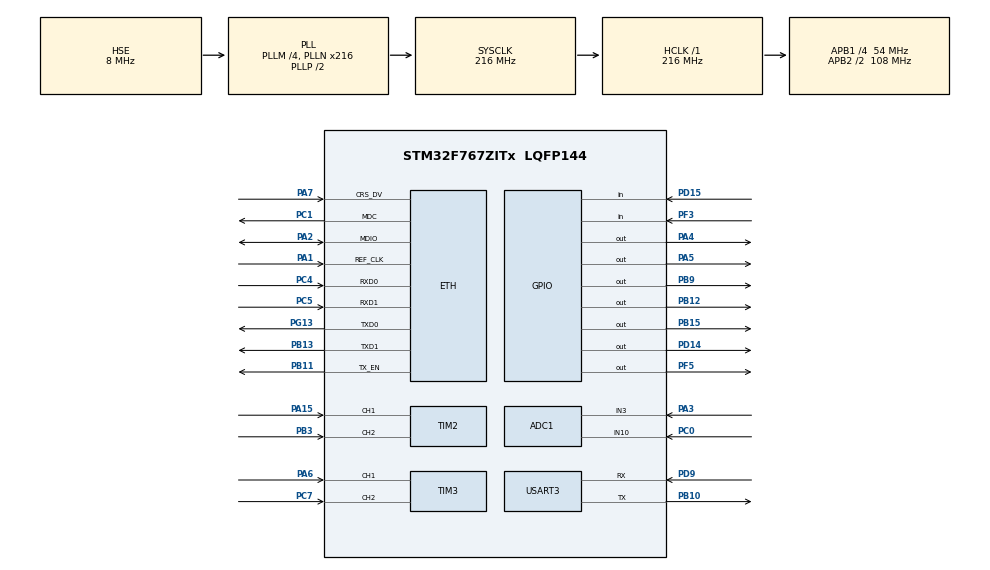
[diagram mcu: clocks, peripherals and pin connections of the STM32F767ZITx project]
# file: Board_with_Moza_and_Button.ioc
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ADC1.Channel-0\#ChannelRegularConversion=ADC_CHANNEL_3
ADC1.ClockPrescaler=ADC_CLOCK_SYNC_PCLK_DIV6
ADC1.NbrOfConversion=1
ADC1.NbrOfConversionFlag=1
ADC1.Rank-0\#ChannelRegularConversion=1
ADC1.SamplingTime-0\#ChannelRegularConversion=ADC_SAMPLETIME_3CYCLES
ADC1.master=1
CORTEX_M7.default_mode_Activation=1
ETH.MediaInterface=HAL_ETH_RMII_MODE
LWIP.BSP.number=1
LWIP.LWIP_DHCP=0
LWIP.Version=v2.1.2_Cube
LWIP0.BSP.STBoard=false
LWIP0.BSP.api=BSP_COMPONENT_DRIVER
LWIP0.BSP.component=LAN8742
LWIP0.BSP.instance=LAN8742
LWIP0.BSP.name=Driver_PHY
LWIP0.BSP.semaphore=S_LAN8742
LWIP0.BSP.solution=LAN8742
Mcu.Family=STM32F7
Mcu.Name=STM32F767ZITx
Mcu.Package=LQFP144
NVIC.PriorityGroup=NVIC_PRIORITYGROUP_4
PA1.Mode=RMII
PA1.Signal=ETH_REF_CLK
PA15.GPIO_PuPd=GPIO_PULLUP
PA15.Signal=S_TIM2_CH1_ETR
PA2.Mode=RMII
PA2.Signal=ETH_MDIO
PA3.Signal=ADCx_IN3
PA4.PinState=GPIO_PIN_SET
PA4.Signal=GPIO_Output
PA5.Signal=GPIO_Output
PA6.GPIO_PuPd=GPIO_PULLUP
PA6.Signal=S_TIM3_CH1
PA7.Mode=RMII
PA7.Signal=ETH_CRS_DV
PB10.Mode=Asynchronous
PB10.Signal=USART3_TX
PB11.Mode=RMII
PB11.Signal=ETH_TX_EN
PB12.PinState=GPIO_PIN_SET
PB12.Signal=GPIO_Output
PB13.Mode=RMII
PB13.Signal=ETH_TXD1
PB15.Signal=GPIO_Output
PB3.GPIO_PuPd=GPIO_PULLUP
PB3.Signal=S_TIM2_CH2
PB9.PinState=GPIO_PIN_SET
PB9.Signal=GPIO_Output
PC0.Signal=ADCx_IN10
PC1.Mode=RMII
PC1.Signal=ETH_MDC
PC4.Mode=RMII
PC4.Signal=ETH_RXD0
PC5.Mode=RMII
PC5.Signal=ETH_RXD1
PC7.GPIO_PuPd=GPIO_PULLUP
PC7.Signal=S_TIM3_CH2
PD14.PinState=GPIO_PIN_SET
PD14.Signal=GPIO_Output
PD15.GPIO_PuPd=GPIO_PULLUP
PD15.Signal=GPIO_Input
PD9.Mode=Asynchronous
PD9.Signal=USART3_RX
PF3.Signal=GPIO_Input
PF5.Signal=GPIO_Output
PG13.Mode=RMII
PG13.Signal=ETH_TXD0
PH0/OSC_IN.Mode=HSE-External-Clock-Source
PH0/OSC_IN.Signal=RCC_OSC_IN
PH1/OSC_OUT.Mode=HSE-External-Clock-Source
PH1/OSC_OUT.Signal=RCC_OSC_OUT
ProjectManager.HeapSize=0x200
ProjectManager.StackSize=0x400
ProjectManager.TargetToolchain=STM32CubeIDE
RCC.AHBFreq_Value=216000000
RCC.APB1CLKDivider=RCC_HCLK_DIV4
RCC.APB1Freq_Value=54000000
RCC.APB1TimFreq_Value=108000000
RCC.APB2CLKDivider=RCC_HCLK_DIV2
RCC.APB2Freq_Value=108000000
RCC.APB2TimFreq_Value=216000000
RCC.CortexFreq_Value=216000000
RCC.HCLKFreq_Value=216000000
RCC.HSE_VALUE=8000000
RCC.HSI_VALUE=16000000
RCC.LSE_VALUE=32768
RCC.PLLM=4
RCC.PLLN=216
RCC.PLLSourceVirtual=RCC_PLLSOURCE_HSE
RCC.SYSCLKFreq_VALUE=216000000
RCC.SYSCLKSource=RCC_SYSCLKSOURCE_PLLCLK
RCC.USBFreq_Value=216000000
RCC.VCOOutputFreq_Value=432000000
SH.ADCx_IN10.0=ADC1_IN10,IN10
SH.ADCx_IN3.0=ADC1_IN3,IN3
SH.S_TIM2_CH1_ETR.0=TIM2_CH1,Encoder_Interface
SH.S_TIM2_CH2.0=TIM2_CH2,Encoder_Interface
SH.S_TIM3_CH1.0=TIM3_CH1,Encoder_Interface
SH.S_TIM3_CH2.0=TIM3_CH2,Encoder_Interface
TIM3.EncoderMode=TIM_ENCODERMODE_TI12
USART3.VirtualMode-Asynchronous=VM_ASYNC
VP_LWIP_VS_Enabled.Mode=Enabled
board=custom

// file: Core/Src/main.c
/* USER CODE BEGIN Header */
/**
  ******************************************************************************
  * @file           : main.c
  * @brief          : Sim Rig Controller - Moza pedals (TLE5012 halls + HX711)
  *
  * Pin map (pedals + shifter, shared SSC bus):
  *   SCK   PA5      DATA  PB15
  *   CS Throttle PA4   CS Clutch PB9   CS Brake PB12   CS Gearbox PD14
  *   HX711 DOUT PF3    HX711 SCK PF5
  * Encoders: TIM2 -> PA15/PB3 (Left), TIM3 -> PA6/PC7 (Right)
  * Gearbox halls: H1 PA3 (ADC1_IN3), H2 PC0 (ADC1_IN10)
  ******************************************************************************
  */
/* USER CODE END Header */

#include "main.h"
#include "lwip.h"
#include <stdlib.h>

/* USER CODE BEGIN Includes */
#include "udp_server.h"
#include <stdio.h>
#include "Tle5012b.h"
#include "hx711.h"
/* USER CODE END Includes */

/* USER CODE BEGIN PD */
/* Moza pedal calibration (angles in degrees from TLE5012) */
#define THROTTLE_ANGLE_MIN     -138.23f
#define THROTTLE_ANGLE_MAX     -118.54f
#define CLUTCH_ANGLE_MIN       -5.83f
#define CLUTCH_ANGLE_MAX       13.16f
#define BRAKE_HALL_ANGLE_MIN   -133.11f
#define BRAKE_HALL_ANGLE_MAX   -121.36f
#define BRAKE_LOADCELL_MIN     -420000
#define BRAKE_LOADCELL_MAX     3600000
#define BRAKE_LOADCELL_TRUST   0.5f

#define RIGHT_STICK_MIN   0
#define RIGHT_STICK_MAX   -475

#define LEFT_STICK_MIN    0
#define LEFT_STICK_MAX    490
/* USER CODE END PD */

ADC_HandleTypeDef hadc1;

UART_HandleTypeDef huart3;

TIM_HandleTypeDef htim2; // Left encoder
TIM_HandleTypeDef htim3; // Right encoder

/* USER CODE BEGIN PV */
/* Global Variables exported to UDP/System (names/types unchanged) */
volatile int32_t current_gear = 0;
volatile int32_t encoder_position = 0;  // Left  (TIM2)
volatile int32_t encoder2_position = 0; // Right (TIM3)

volatile int32_t accelerator_position = 0; // throttle angle * 100
volatile int32_t brake_position = 0;       // filtered load cell raw
volatile int32_t clutch_position = 0;      // clutch angle * 100

volatile int32_t button_state = 0; // 0 = Released, 1 = Pressed

volatile float right_stick_scaled = 0.0f;
volatile float left_stick_scaled  = 0.0f;
volatile float accelerator_scaled = 0.0f;
volatile float brake_scaled       = 0.0f;   // final blended brake (hall + load cell)
volatile float clutch_scaled      = 0.0f;
volatile float min_clutch_pressed = 0.8f;

uint32_t H1_ADC = 0;
uint32_t H2_ADC = 0;

/* Pedal sensor data */
static float throttle_angle   = 0.0f;
static float clutch_angle     = 0.0f;
static float brake_hall_angle = 0.0f;
static float brake_hall_scaled = 0.0f;
static TLE5012_Frame_t throttle_frame, clutch_frame, brake_hall_frame;

static int32_t loadcell_filtered = 0;
static uint8_t loadcell_filter_init = 0;

/* Internal Loop State Variables */
static uint32_t last_tick_ms = 0;
static uint32_t last_led_tick_ms = 0;
static uint32_t last_uart_tick_ms = 0;

static uint16_t last_timer = 0;
static uint16_t last_timer2 = 0;

static uint32_t h1_filtered = 0, h2_filtered = 0;
static uint8_t  h1_filter_init = 0, h2_filter_init = 0;

static int32_t last_valid_gear = 0;
static int32_t last_requested_gear = 0;

static int32_t h_fused = 0;
/* USER CODE END PV */

void SystemClock_Config(void);
static void MPU_Config(void);
static void MX_GPIO_Init(void);
static void MX_ADC1_Init(void);
static void MX_TIM2_Init(void);
static void MX_TIM3_Init(void);
static void MX_USART3_UART_Init(void);

/* USER CODE BEGIN PFP */
static uint32_t read_adc_channel(ADC_HandleTypeDef *hadc, uint32_t channel);
static float scale_clamped_0_1(float value, float min_val, float max_val);
static void read_pedal_angle(const TLE5012_Sensor_t *s, float *angle, TLE5012_Frame_t *frame);
static int32_t compute_gear(float x_raw, int32_t y_raw);
/* USER CODE END PFP */

/* USER CODE BEGIN 0 */
static uint32_t read_adc_channel(ADC_HandleTypeDef *hadc, uint32_t channel)
{
    ADC_ChannelConfTypeDef sConfig = {0};
    sConfig.Channel = channel;
    sConfig.Rank = ADC_REGULAR_RANK_1;
    sConfig.SamplingTime = ADC_SAMPLETIME_56CYCLES;
    HAL_ADC_ConfigChannel(hadc, &sConfig);

    HAL_ADC_Start(hadc);
    HAL_ADC_PollForConversion(hadc, 10);
    uint32_t raw = HAL_ADC_GetValue(hadc);
    HAL_ADC_Stop(hadc);

    return raw;
}

/* Works for both min<max and min>max (reversed) ranges */
static float scale_clamped_0_1(float value, float min_val, float max_val)
{
    if (min_val == max_val) return 0.0f;

    float lo = (min_val < max_val) ? min_val : max_val;
    float hi = (min_val < max_val) ? max_val : min_val;
    if (value < lo) value = lo;
    if (value > hi) value = hi;

    return (value - min_val) / (max_val - min_val);
}

/* Reads a TLE5012 angle; keeps the previous angle if the CRC check fails */
static void read_pedal_angle(const TLE5012_Sensor_t *s, float *angle, TLE5012_Frame_t *frame)
{
    float a = 0.0f;
    TLE5012_Frame_t f;
    if (TLE5012_ReadAngleDeg(s, &a, &f) == HAL_OK && f.crc_ok) {
        *angle = a;
    }
    *frame = f;
}

static int classify_row(int32_t y)
{
    if (y < -1500) return -1;      /* top (front) */
    else if (y > 1500) return 1;   /* neutral */
    else return 0;                 /* bottom (back) */
}

static int classify_col(float x)
{
    if (x < -58.0f) return -1;     /* left */
    else if (x < -48.0f) return 0; /* center */
    else return 1;                 /* right */
}

static int32_t compute_gear(float x_raw, int32_t y_raw)
{
    int col = classify_col(x_raw);
    int row = classify_row(y_raw);

    if (row == 0) return 0;

    if (row == -1) {
        if (col == -1) return 3;
        if (col == 0)  return 6;
        if (col == 1)  return 4;
    }

    if (row == 1) {
        if (col == -1) return 2;
        if (col == 0)  return 1;
        if (col == 1)  return 5;
    }

    return 0;
}
/* USER CODE END 0 */

int main(void)
{
  TLE5012_Frame_t frame = {0};
  float angle_deg = 0.0f;

  MPU_Config();
  HAL_Init();
  SystemClock_Config();

  /* Peripheral Initialization */
  MX_GPIO_Init();
  MX_ADC1_Init();
  MX_TIM2_Init();
  MX_TIM3_Init();
  MX_USART3_UART_Init();
  MX_LWIP_Init();

  HAL_Delay(500);

  /* Start Hardware Timers for Quadrature Encoders */
  HAL_TIM_Encoder_Start(&htim2, TIM_CHANNEL_ALL); // Left
  HAL_TIM_Encoder_Start(&htim3, TIM_CHANNEL_ALL); // Right
  last_timer  = (uint16_t)__HAL_TIM_GET_COUNTER(&htim2);
  last_timer2 = (uint16_t)__HAL_TIM_GET_COUNTER(&htim3);

  /* Initialize Communication and Driver Peripherals */
  udp_server_init();
  TLE5012_GPIO_Init();   /* SCK/DATA + 4 CS lines (idle HIGH) + DWT */
  HX711_Init();          /* PF5 SCK, PF3 DOUT */

  uint32_t init_tick = HAL_GetTick();
  last_tick_ms      = init_tick;
  last_led_tick_ms  = init_tick;
  last_uart_tick_ms = init_tick;

  while (1)
  {
      MX_LWIP_Process();
      uint32_t now = HAL_GetTick();

      /* 1. Heartbeat LED (500ms Period) */
      if ((now - last_led_tick_ms) >= 500) {
          HAL_GPIO_TogglePin(LD2_GPIO_Port, LD2_Pin);
          last_led_tick_ms = now;
      }

      /* 2. Main Input Sampling Loop (10ms / 100Hz Rate) */
      if ((now - last_tick_ms) >= 10)
      {
          last_tick_ms = now;

          /* Push Button on PD15 (Active Low) */
          button_state = (HAL_GPIO_ReadPin(GPIOD, GPIO_PIN_15) == GPIO_PIN_RESET) ? 1 : 0;

          /* Left Encoder (TIM2) */
          uint16_t current_timer = (uint16_t)__HAL_TIM_GET_COUNTER(&htim2);
          encoder_position += (int16_t)(current_timer - last_timer);
          last_timer = current_timer;

          /* Right Encoder (TIM3) */
          uint16_t current_timer2 = (uint16_t)__HAL_TIM_GET_COUNTER(&htim3);
          encoder2_position += (int16_t)(current_timer2 - last_timer2);
          last_timer2 = current_timer2;

          /* ---------- Moza pedals ---------- */
          read_pedal_angle(&TLE5012_THROTTLE,   &throttle_angle,   &throttle_frame);
          read_pedal_angle(&TLE5012_CLUTCH,     &clutch_angle,     &clutch_frame);
          read_pedal_angle(&TLE5012_BRAKE_HALL, &brake_hall_angle, &brake_hall_frame);

          /* Load cell: non-blocking, only reads when a conversion is ready */
          int32_t lc_raw;
          if (HX711_TryRead(HX711_CHA_GAIN_128, &lc_raw)) {
              if (!loadcell_filter_init) { loadcell_filtered = lc_raw; loadcell_filter_init = 1; }
              else { loadcell_filtered += (lc_raw - loadcell_filtered) / 8; }
          }

          brake_hall_scaled = scale_clamped_0_1(brake_hall_angle,
                                                BRAKE_HALL_ANGLE_MIN, BRAKE_HALL_ANGLE_MAX);
          float loadcell_scaled = scale_clamped_0_1((float)loadcell_filtered,
                                                    BRAKE_LOADCELL_MIN, BRAKE_LOADCELL_MAX);

          accelerator_scaled = scale_clamped_0_1(throttle_angle, THROTTLE_ANGLE_MIN, THROTTLE_ANGLE_MAX);
          clutch_scaled      = scale_clamped_0_1(clutch_angle,   CLUTCH_ANGLE_MIN,   CLUTCH_ANGLE_MAX);
          brake_scaled       = brake_hall_scaled * (1.0f - BRAKE_LOADCELL_TRUST)
                             + loadcell_scaled   * BRAKE_LOADCELL_TRUST;

          /* Keep the raw-position fields populated for UDP/debug users */
          accelerator_position = (int32_t)(throttle_angle * 100.0f);
          clutch_position      = (int32_t)(clutch_angle   * 100.0f);
          brake_position       = loadcell_filtered;

          /* Encoder Normalization */
          left_stick_scaled  = scale_clamped_0_1((float)encoder_position,  LEFT_STICK_MIN,  LEFT_STICK_MAX);  // TIM2 = Left
          right_stick_scaled = scale_clamped_0_1((float)encoder2_position, RIGHT_STICK_MIN, RIGHT_STICK_MAX); // TIM3 = Right

          /* Gearbox Hall Sensors */
          H1_ADC = read_adc_channel(&hadc1, ADC_CHANNEL_3);
          H2_ADC = read_adc_channel(&hadc1, ADC_CHANNEL_10);

          if (!h1_filter_init) { h1_filtered = H1_ADC; h1_filter_init = 1; }
          else { h1_filtered = h1_filtered + ((int32_t)H1_ADC - (int32_t)h1_filtered) / 3; }

          if (!h2_filter_init) { h2_filtered = H2_ADC; h2_filter_init = 1; }
          else { h2_filtered = h2_filtered + ((int32_t)H2_ADC - (int32_t)h2_filtered) / 3; }

          h_fused = (int32_t)h1_filtered - (int32_t)h2_filtered;

          /* TLE5012 Shifter Angle Decoding */
          if (TLE5012_ReadAngleDeg(&TLE5012_GEARBOX, &angle_deg, &frame) == HAL_OK && frame.crc_ok) {
              int32_t requested_gear = compute_gear(angle_deg, h_fused);

              if (requested_gear != last_requested_gear) {
                  if (clutch_scaled >= min_clutch_pressed) {
                      last_valid_gear = requested_gear;
                  }
                  last_requested_gear = requested_gear;
              }
              current_gear = last_valid_gear;
          }
          else {
              current_gear = last_valid_gear;
          }

          udp_server_send_position();
      }

      /* 3. Debug Output via UART3 (200ms Rate) */
      if ((now - last_uart_tick_ms) >= 200) {
          last_uart_tick_ms = now;
          char dbg[360];
          int dbg_len = snprintf(dbg, sizeof(dbg),
              "Acc:%.2f (Ang:%.2f CRC:%u) Clt:%.2f (Ang:%.2f CRC:%u) "
              "Brk:%.2f (Hall:%.2f Ang:%.2f CRC:%u LC:%ld) "
              "H1:%lu H2:%lu h_fused:%ld Angle:%.2f Gear:%ld "
              "RT:%.2f (Raw2:%ld) LT:%.2f (Raw:%ld) Btn:%ld\r\n",
              accelerator_scaled, throttle_angle, throttle_frame.crc_ok,
              clutch_scaled, clutch_angle, clutch_frame.crc_ok,
              brake_scaled, brake_hall_scaled, brake_hall_angle, brake_hall_frame.crc_ok,
              (long)loadcell_filtered,
              H1_ADC, H2_ADC, (long)h_fused, angle_deg, (long)current_gear,
              right_stick_scaled, (long)encoder2_position,
              left_stick_scaled, (long)encoder_position, (long)button_state);
          if (dbg_len > (int)sizeof(dbg)) dbg_len = sizeof(dbg);
          HAL_UART_Transmit(&huart3, (uint8_t*)dbg, dbg_len, 50);
      }
  }
}

void SystemClock_Config(void)
{
  RCC_OscInitTypeDef RCC_OscInitStruct = {0};
  RCC_ClkInitTypeDef RCC_ClkInitStruct = {0};

  HAL_PWR_EnableBkUpAccess();
  __HAL_RCC_PWR_CLK_ENABLE();
  __HAL_PWR_VOLTAGESCALING_CONFIG(PWR_REGULATOR_VOLTAGE_SCALE1);

  RCC_OscInitStruct.OscillatorType = RCC_OSCILLATORTYPE_HSE;
  RCC_OscInitStruct.HSEState = RCC_HSE_BYPASS;
  RCC_OscInitStruct.PLL.PLLState = RCC_PLL_ON;
  RCC_OscInitStruct.PLL.PLLSource = RCC_PLLSOURCE_HSE;
  RCC_OscInitStruct.PLL.PLLM = 4;
  RCC_OscInitStruct.PLL.PLLN = 216;
  RCC_OscInitStruct.PLL.PLLP = RCC_PLLP_DIV2;
  RCC_OscInitStruct.PLL.PLLQ = 9;
  RCC_OscInitStruct.PLL.PLLR = 2;

  // Retry until the external MCO/HSE is actually present
  while (HAL_RCC_OscConfig(&RCC_OscInitStruct) != HAL_OK)
  {
      HAL_Delay(5); // safe: still running off default HSI here
  }

  if (HAL_PWREx_EnableOverDrive() != HAL_OK) { Error_Handler(); }

  RCC_ClkInitStruct.ClockType = RCC_CLOCKTYPE_HCLK|RCC_CLOCKTYPE_SYSCLK
                              |RCC_CLOCKTYPE_PCLK1|RCC_CLOCKTYPE_PCLK2;
  RCC_ClkInitStruct.SYSCLKSource = RCC_SYSCLKSOURCE_PLLCLK;
  RCC_ClkInitStruct.AHBCLKDivider = RCC_SYSCLK_DIV1;
  RCC_ClkInitStruct.APB1CLKDivider = RCC_HCLK_DIV4;
  RCC_ClkInitStruct.APB2CLKDivider = RCC_HCLK_DIV2;

  while (HAL_RCC_ClockConfig(&RCC_ClkInitStruct, FLASH_LATENCY_7) != HAL_OK)
  {
      HAL_Delay(5);
  }
}

/* ADC1: gearbox hall sensors only (H1 = CH3, H2 = CH10, switched at runtime) */
static void MX_ADC1_Init(void)
{
  ADC_ChannelConfTypeDef sConfig = {0};

  hadc1.Instance = ADC1;
  hadc1.Init.ClockPrescaler = ADC_CLOCK_SYNC_PCLK_DIV6;
  hadc1.Init.Resolution = ADC_RESOLUTION_12B;
  hadc1.Init.ScanConvMode = ADC_SCAN_DISABLE;
  hadc1.Init.ContinuousConvMode = DISABLE;
  hadc1.Init.DiscontinuousConvMode = DISABLE;
  hadc1.Init.ExternalTrigConvEdge = ADC_EXTERNALTRIGCONVEDGE_NONE;
  hadc1.Init.ExternalTrigConv = ADC_SOFTWARE_START;
  hadc1.Init.DataAlign = ADC_DATAALIGN_RIGHT;
  hadc1.Init.NbrOfConversion = 1;
  hadc1.Init.DMAContinuousRequests = DISABLE;
  hadc1.Init.EOCSelection = ADC_EOC_SINGLE_CONV;
  if (HAL_ADC_Init(&hadc1) != HAL_OK)
  {
    Error_Handler();
  }

  sConfig.Channel = ADC_CHANNEL_3;
  sConfig.Rank = ADC_REGULAR_RANK_1;
  sConfig.SamplingTime = ADC_SAMPLETIME_3CYCLES;
  if (HAL_ADC_ConfigChannel(&hadc1, &sConfig) != HAL_OK)
  {
    Error_Handler();
  }
}

static void MX_TIM2_Init(void)
{
  TIM_Encoder_InitTypeDef sConfig = {0};
  TIM_MasterConfigTypeDef sMasterConfig = {0};

  htim2.Instance = TIM2;
  htim2.Init.Prescaler = 0;
  htim2.Init.CounterMode = TIM_COUNTERMODE_UP;
  htim2.Init.Period = 65535;
  htim2.Init.ClockDivision = TIM_CLOCKDIVISION_DIV1;
  htim2.Init.AutoReloadPreload = TIM_AUTORELOAD_PRELOAD_DISABLE;
  sConfig.EncoderMode = TIM_ENCODERMODE_TI12;
  sConfig.IC1Polarity = TIM_ICPOLARITY_RISING;
  sConfig.IC1Selection = TIM_ICSELECTION_DIRECTTI;
  sConfig.IC1Prescaler = TIM_ICPSC_DIV1;
  sConfig.IC1Filter = 0;
  sConfig.IC2Polarity = TIM_ICPOLARITY_RISING;
  sConfig.IC2Selection = TIM_ICSELECTION_DIRECTTI;
  sConfig.IC2Prescaler = TIM_ICPSC_DIV1;
  sConfig.IC2Filter = 0;
  if (HAL_TIM_Encoder_Init(&htim2, &sConfig) != HAL_OK)
  {
    Error_Handler();
  }
  sMasterConfig.MasterOutputTrigger = TIM_TRGO_RESET;
  sMasterConfig.MasterSlaveMode = TIM_MASTERSLAVEMODE_DISABLE;
  if (HAL_TIMEx_MasterConfigSynchronization(&htim2, &sMasterConfig) != HAL_OK)
  {
    Error_Handler();
  }
}

static void MX_TIM3_Init(void)
{
  TIM_Encoder_InitTypeDef sConfig = {0};
  TIM_MasterConfigTypeDef sMasterConfig = {0};

  htim3.Instance = TIM3;
  htim3.Init.Prescaler = 0;
  htim3.Init.CounterMode = TIM_COUNTERMODE_UP;
  htim3.Init.Period = 65535;
  htim3.Init.ClockDivision = TIM_CLOCKDIVISION_DIV1;
  htim3.Init.AutoReloadPreload = TIM_AUTORELOAD_PRELOAD_DISABLE;
  sConfig.EncoderMode = TIM_ENCODERMODE_TI12;
  sConfig.IC1Polarity = TIM_ICPOLARITY_RISING;
  sConfig.IC1Selection = TIM_ICSELECTION_DIRECTTI;
  sConfig.IC1Prescaler = TIM_ICPSC_DIV1;
  sConfig.IC1Filter = 0;
  sConfig.IC2Polarity = TIM_ICPOLARITY_RISING;
  sConfig.IC2Selection = TIM_ICSELECTION_DIRECTTI;
  sConfig.IC2Prescaler = TIM_ICPSC_DIV1;
  sConfig.IC2Filter = 0;
  if (HAL_TIM_Encoder_Init(&htim3, &sConfig) != HAL_OK)
  {
    Error_Handler();
  }
  sMasterConfig.MasterOutputTrigger = TIM_TRGO_RESET;
  sMasterConfig.MasterSlaveMode = TIM_MASTERSLAVEMODE_DISABLE;
  if (HAL_TIMEx_MasterConfigSynchronization(&htim3, &sMasterConfig) != HAL_OK)
  {
    Error_Handler();
  }
}

static void MX_USART3_UART_Init(void)
{
  huart3.Instance = USART3;
  huart3.Init.BaudRate = 115200;
  huart3.Init.WordLength = UART_WORDLENGTH_8B;
  huart3.Init.StopBits = UART_STOPBITS_1;
  huart3.Init.Parity = UART_PARITY_NONE;
  huart3.Init.Mode = UART_MODE_TX_RX;
  huart3.Init.HwFlowCtl = UART_HWCONTROL_NONE;
  huart3.Init.OverSampling = UART_OVERSAMPLING_16;
  huart3.Init.OneBitSampling = UART_ONE_BIT_SAMPLE_DISABLE;
  huart3.AdvancedInit.AdvFeatureInit = UART_ADVFEATURE_NO_INIT;
  if (HAL_UART_Init(&huart3) != HAL_OK)
  {
    Error_Handler();
  }
}

static void MX_GPIO_Init(void)
{
  GPIO_InitTypeDef GPIO_InitStruct = {0};

  __HAL_RCC_GPIOC_CLK_ENABLE();
  __HAL_RCC_GPIOF_CLK_ENABLE();
  __HAL_RCC_GPIOH_CLK_ENABLE();
  __HAL_RCC_GPIOA_CLK_ENABLE();
  __HAL_RCC_GPIOB_CLK_ENABLE();
  __HAL_RCC_GPIOD_CLK_ENABLE();
  __HAL_RCC_GPIOG_CLK_ENABLE();
  __HAL_RCC_SYSCFG_CLK_ENABLE();

  HAL_GPIO_WritePin(GPIOB, LD1_Pin|LD3_Pin|LD2_Pin, GPIO_PIN_RESET);
  /* PD14 = Gearbox TLE5012 CS (active LOW) -> idle HIGH (deselected) */
  HAL_GPIO_WritePin(GPIOD, GPIO_PIN_14, GPIO_PIN_SET);
  HAL_GPIO_WritePin(USB_PowerSwitchOn_GPIO_Port, USB_PowerSwitchOn_Pin, GPIO_PIN_RESET);

  /* Configure PD15 as Input with Internal Pull-Up for Push Button */
  GPIO_InitStruct.Pin = GPIO_PIN_15;
  GPIO_InitStruct.Mode = GPIO_MODE_INPUT;
  GPIO_InitStruct.Pull = GPIO_PULLUP;
  HAL_GPIO_Init(GPIOD, &GPIO_InitStruct);

  GPIO_InitStruct.Pin = LD1_Pin|LD3_Pin|LD2_Pin;
  GPIO_InitStruct.Mode = GPIO_MODE_OUTPUT_PP;
  GPIO_InitStruct.Pull = GPIO_NOPULL;
  GPIO_InitStruct.Speed = GPIO_SPEED_FREQ_LOW;
  HAL_GPIO_Init(GPIOB, &GPIO_InitStruct);

  GPIO_InitStruct.Pin = GPIO_PIN_14;
  GPIO_InitStruct.Mode = GPIO_MODE_OUTPUT_PP;
  GPIO_InitStruct.Pull = GPIO_NOPULL;
  GPIO_InitStruct.Speed = GPIO_SPEED_FREQ_LOW;
  HAL_GPIO_Init(GPIOD, &GPIO_InitStruct);

  GPIO_InitStruct.Pin = USB_PowerSwitchOn_Pin;
  GPIO_InitStruct.Mode = GPIO_MODE_OUTPUT_PP;
  GPIO_InitStruct.Pull = GPIO_NOPULL;
  GPIO_InitStruct.Speed = GPIO_SPEED_FREQ_LOW;
  HAL_GPIO_Init(USB_PowerSwitchOn_GPIO_Port, &GPIO_InitStruct);

  /* Analog input: H1 PA3 (ADC1_IN3).
   * PA4 is now Throttle CS (configured by TLE5012_GPIO_Init). */
  GPIO_InitStruct.Pin = GPIO_PIN_3;
  GPIO_InitStruct.Mode = GPIO_MODE_ANALOG;
  GPIO_InitStruct.Pull = GPIO_NOPULL;
  HAL_GPIO_Init(GPIOA, &GPIO_InitStruct);

  /* Analog input: H2 PC0 (ADC1_IN10) */
  GPIO_InitStruct.Pin = GPIO_PIN_0;
  GPIO_InitStruct.Mode = GPIO_MODE_ANALOG;
  GPIO_InitStruct.Pull = GPIO_NOPULL;
  HAL_GPIO_Init(GPIOC, &GPIO_InitStruct);

  /* PF3 / PF5 (HX711) and PA5 / PB15 / PA4 / PB9 / PB12 (TLE5012 bus + CS)
   * are configured by HX711_Init() and TLE5012_GPIO_Init(). */

  /* ================================================================ */
  /* ENCODER PINS - MUST match stm32f7xx_hal_msp.c                    */
  /* TIM3 (Right): PA6 = CH1, PC7 = CH2, AF2_TIM3                     */
  /* TIM2 (Left):  PA15 = CH1, PB3 = CH2, AF1_TIM2                    */
  /* ================================================================ */

  GPIO_InitStruct.Pin = GPIO_PIN_6;
  GPIO_InitStruct.Mode = GPIO_MODE_AF_PP;
  GPIO_InitStruct.Pull = GPIO_PULLUP;
  GPIO_InitStruct.Speed = GPIO_SPEED_FREQ_HIGH;
  GPIO_InitStruct.Alternate = GPIO_AF2_TIM3;
  HAL_GPIO_Init(GPIOA, &GPIO_InitStruct);

  GPIO_InitStruct.Pin = GPIO_PIN_7;
  GPIO_InitStruct.Mode = GPIO_MODE_AF_PP;
  GPIO_InitStruct.Pull = GPIO_PULLUP;
  GPIO_InitStruct.Speed = GPIO_SPEED_FREQ_HIGH;
  GPIO_InitStruct.Alternate = GPIO_AF2_TIM3;
  HAL_GPIO_Init(GPIOC, &GPIO_InitStruct);

  GPIO_InitStruct.Pin = GPIO_PIN_15;
  GPIO_InitStruct.Mode = GPIO_MODE_AF_PP;
  GPIO_InitStruct.Pull = GPIO_PULLUP;
  GPIO_InitStruct.Speed = GPIO_SPEED_FREQ_HIGH;
  GPIO_InitStruct.Alternate = GPIO_AF1_TIM2;
  HAL_GPIO_Init(GPIOA, &GPIO_InitStruct);

  GPIO_InitStruct.Pin = GPIO_PIN_3;
  GPIO_InitStruct.Mode = GPIO_MODE_AF_PP;
  GPIO_InitStruct.Pull = GPIO_PULLUP;
  GPIO_InitStruct.Speed = GPIO_SPEED_FREQ_HIGH;
  GPIO_InitStruct.Alternate = GPIO_AF1_TIM2;
  HAL_GPIO_Init(GPIOB, &GPIO_InitStruct);
}

void MPU_Config(void)
{
  MPU_Region_InitTypeDef MPU_InitStruct = {0};

  HAL_MPU_Disable();

  MPU_InitStruct.Enable = MPU_REGION_ENABLE;
  MPU_InitStruct.Number = MPU_REGION_NUMBER0;
  MPU_InitStruct.BaseAddress = 0x0;
  MPU_InitStruct.Size = MPU_REGION_SIZE_4GB;
  MPU_InitStruct.SubRegionDisable = 0x87;
  MPU_InitStruct.TypeExtField = MPU_TEX_LEVEL0;
  MPU_InitStruct.AccessPermission = MPU_REGION_NO_ACCESS;
  MPU_InitStruct.DisableExec = MPU_INSTRUCTION_ACCESS_DISABLE;
  MPU_InitStruct.IsShareable = MPU_ACCESS_SHAREABLE;
  MPU_InitStruct.IsCacheable = MPU_ACCESS_NOT_CACHEABLE;
  MPU_InitStruct.IsBufferable = MPU_ACCESS_NOT_BUFFERABLE;

  HAL_MPU_ConfigRegion(&MPU_InitStruct);
  HAL_MPU_Enable(MPU_PRIVILEGED_DEFAULT);
}

void Error_Handler(void)
{
  __disable_irq();
  while (1)
  {
  }
}
